VERSION 5.7 ;
  NOWIREEXTENSIONATPIN ON ;
  DIVIDERCHAR "/" ;
  BUSBITCHARS "[]" ;
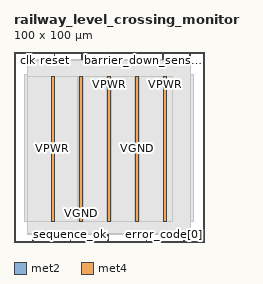
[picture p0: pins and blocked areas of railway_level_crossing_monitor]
MACRO railway_level_crossing_monitor
  CLASS BLOCK ;
  FOREIGN railway_level_crossing_monitor ;
  ORIGIN 0.000 0.000 ;
  SIZE 100.000 BY 100.000 ;
  PIN barrier_down_sensor
    DIRECTION INPUT ;
    USE SIGNAL ;
    PORT
      LAYER met2 ;
        RECT 78.290 96.000 78.570 100.000 ;
    END
  END barrier_down_sensor
  PIN barrier_up_sensor
    DIRECTION INPUT ;
    USE SIGNAL ;
    PORT
      LAYER met2 ;
        RECT 92.550 96.000 92.830 100.000 ;
    END
  END barrier_up_sensor
  PIN clk
    DIRECTION INPUT ;
    USE SIGNAL ;
    PORT
      LAYER met2 ;
        RECT 6.990 96.000 7.270 100.000 ;
    END
  END clk
  PIN error_code[0]
    DIRECTION OUTPUT TRISTATE ;
    USE SIGNAL ;
    PORT
      LAYER met2 ;
        RECT 89.330 0.000 89.610 4.000 ;
    END
  END error_code[0]
  PIN error_code[1]
    DIRECTION OUTPUT TRISTATE ;
    USE SIGNAL ;
    PORT
      LAYER met2 ;
        RECT 69.550 0.000 69.830 4.000 ;
    END
  END error_code[1]
  PIN error_code[2]
    DIRECTION OUTPUT TRISTATE ;
    USE SIGNAL ;
    PORT
      LAYER met2 ;
        RECT 49.310 0.000 49.590 4.000 ;
    END
  END error_code[2]
  PIN fail_safe
    DIRECTION OUTPUT TRISTATE ;
    USE SIGNAL ;
    PORT
      LAYER met2 ;
        RECT 9.750 0.000 10.030 4.000 ;
    END
  END fail_safe
  PIN light_on_sensor
    DIRECTION INPUT ;
    USE SIGNAL ;
    PORT
      LAYER met2 ;
        RECT 64.030 96.000 64.310 100.000 ;
    END
  END light_on_sensor
  PIN reset
    DIRECTION INPUT ;
    USE SIGNAL ;
    PORT
      LAYER met2 ;
        RECT 21.250 96.000 21.530 100.000 ;
    END
  END reset
  PIN sequence_ok
    DIRECTION OUTPUT TRISTATE ;
    USE SIGNAL ;
    PORT
      LAYER met2 ;
        RECT 29.530 0.000 29.810 4.000 ;
    END
  END sequence_ok
  PIN train_approach
    DIRECTION INPUT ;
    USE SIGNAL ;
    PORT
      LAYER met2 ;
        RECT 35.510 96.000 35.790 100.000 ;
    END
  END train_approach
  PIN train_depart
    DIRECTION INPUT ;
    USE SIGNAL ;
    PORT
      LAYER met2 ;
        RECT 49.770 96.000 50.050 100.000 ;
    END
  END train_depart
  PIN VPWR
    DIRECTION INOUT ;
    USE POWER ;
    PORT
      LAYER met4 ;
        RECT 78.855 10.640 80.455 87.280 ;
    END
  END VPWR
  PIN VPWR
    DIRECTION INOUT ;
    USE POWER ;
    PORT
      LAYER met4 ;
        RECT 49.200 10.640 50.800 87.280 ;
    END
  END VPWR
  PIN VPWR
    DIRECTION INOUT ;
    USE POWER ;
    PORT
      LAYER met4 ;
        RECT 19.545 10.640 21.145 87.280 ;
    END
  END VPWR
  PIN VGND
    DIRECTION INOUT ;
    USE GROUND ;
    PORT
      LAYER met4 ;
        RECT 64.025 10.640 65.625 87.280 ;
    END
  END VGND
  PIN VGND
    DIRECTION INOUT ;
    USE GROUND ;
    PORT
      LAYER met4 ;
        RECT 34.375 10.640 35.975 87.280 ;
    END
  END VGND
  OBS
      LAYER nwell ;
        RECT 5.330 85.625 94.490 87.230 ;
        RECT 5.330 80.185 94.490 83.015 ;
        RECT 5.330 74.745 94.490 77.575 ;
        RECT 5.330 69.305 94.490 72.135 ;
        RECT 5.330 63.865 94.490 66.695 ;
        RECT 5.330 58.425 94.490 61.255 ;
        RECT 5.330 52.985 94.490 55.815 ;
        RECT 5.330 47.545 94.490 50.375 ;
        RECT 5.330 42.105 94.490 44.935 ;
        RECT 5.330 36.665 94.490 39.495 ;
        RECT 5.330 31.225 94.490 34.055 ;
        RECT 5.330 25.785 94.490 28.615 ;
        RECT 5.330 20.345 94.490 23.175 ;
        RECT 5.330 14.905 94.490 17.735 ;
        RECT 5.330 10.690 94.490 12.295 ;
      LAYER li1 ;
        RECT 5.520 10.795 94.300 87.125 ;
      LAYER met1 ;
        RECT 5.520 10.640 94.300 88.360 ;
      LAYER met2 ;
        RECT 7.550 95.720 20.970 96.000 ;
        RECT 21.810 95.720 35.230 96.000 ;
        RECT 36.070 95.720 49.490 96.000 ;
        RECT 50.330 95.720 63.750 96.000 ;
        RECT 64.590 95.720 78.010 96.000 ;
        RECT 78.850 95.720 92.270 96.000 ;
        RECT 6.990 4.280 92.820 95.720 ;
        RECT 6.990 4.000 9.470 4.280 ;
        RECT 10.310 4.000 29.250 4.280 ;
        RECT 30.090 4.000 49.030 4.280 ;
        RECT 49.870 4.000 69.270 4.280 ;
        RECT 70.110 4.000 89.050 4.280 ;
        RECT 89.890 4.000 92.820 4.280 ;
      LAYER met3 ;
        RECT 6.965 10.715 83.195 87.205 ;
      LAYER met4 ;
        RECT 33.415 10.640 33.975 87.280 ;
        RECT 36.375 10.640 48.800 87.280 ;
        RECT 51.200 10.640 63.625 87.280 ;
        RECT 66.025 10.640 78.455 87.280 ;
  END
END railway_level_crossing_monitor
END LIBRARY

